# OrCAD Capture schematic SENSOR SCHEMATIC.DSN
size B

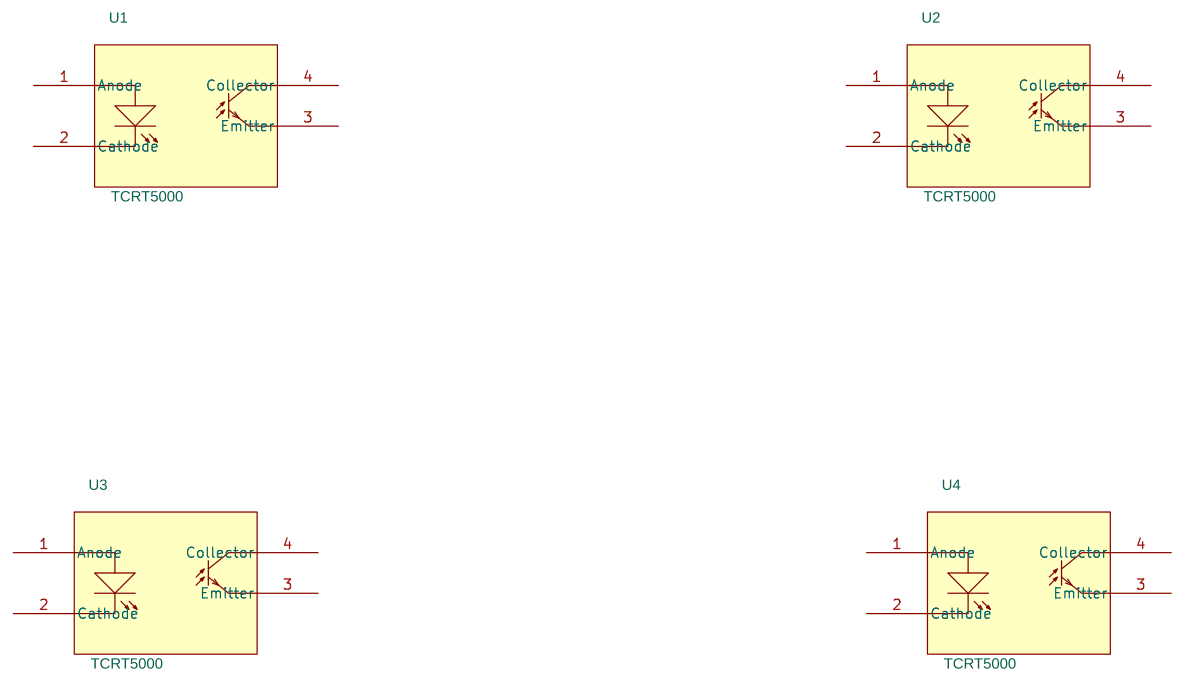
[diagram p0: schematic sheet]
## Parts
U1  TCRT5000  [vishay_tcrt5000]
U2  TCRT5000  [vishay_tcrt5000]
U3  TCRT5000  [vishay_tcrt5000]
U4  TCRT5000  [vishay_tcrt5000]

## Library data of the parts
U1-U4 = TCRT5000

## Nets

Not connected (* = marked no-connect by the designer): U1 1(Anode) 2(Cathode) 3(Emitter) 4(Collector); U2 1(Anode) 2(Cathode) 3(Emitter) 4(Collector); U3 1(Anode) 2(Cathode) 3(Emitter) 4(Collector); U4 1(Anode) 2(Cathode) 3(Emitter) 4(Collector)
